VERSION 5.7 ;
BUSBITCHARS "[]" ;
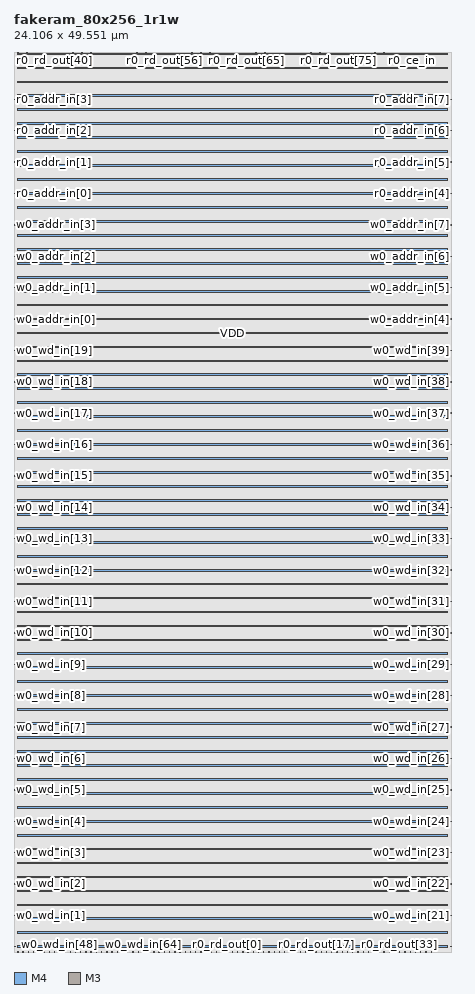
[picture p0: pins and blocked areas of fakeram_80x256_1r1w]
MACRO fakeram_80x256_1r1w
  FOREIGN fakeram_80x256_1r1w 0 0 ;
  SYMMETRY X Y R90 ;
  SIZE 24.106 BY 49.551 ;
  CLASS BLOCK ;
  PIN w0_wd_in[0]
    DIRECTION INPUT ;
    USE SIGNAL ;
    SHAPE ABUTMENT ;
    PORT
      LAYER M4 ;
      RECT 0.000 0.276 0.072 0.300 ;
    END
  END w0_wd_in[0]
  PIN w0_wd_in[1]
    DIRECTION INPUT ;
    USE SIGNAL ;
    SHAPE ABUTMENT ;
    PORT
      LAYER M4 ;
      RECT 0.000 2.004 0.072 2.028 ;
    END
  END w0_wd_in[1]
  PIN w0_wd_in[2]
    DIRECTION INPUT ;
    USE SIGNAL ;
    SHAPE ABUTMENT ;
    PORT
      LAYER M4 ;
      RECT 0.000 3.732 0.072 3.756 ;
    END
  END w0_wd_in[2]
  PIN w0_wd_in[3]
    DIRECTION INPUT ;
    USE SIGNAL ;
    SHAPE ABUTMENT ;
    PORT
      LAYER M4 ;
      RECT 0.000 5.460 0.072 5.484 ;
    END
  END w0_wd_in[3]
  PIN w0_wd_in[4]
    DIRECTION INPUT ;
    USE SIGNAL ;
    SHAPE ABUTMENT ;
    PORT
      LAYER M4 ;
      RECT 0.000 7.188 0.072 7.212 ;
    END
  END w0_wd_in[4]
  PIN w0_wd_in[5]
    DIRECTION INPUT ;
    USE SIGNAL ;
    SHAPE ABUTMENT ;
    PORT
      LAYER M4 ;
      RECT 0.000 8.916 0.072 8.940 ;
    END
  END w0_wd_in[5]
  PIN w0_wd_in[6]
    DIRECTION INPUT ;
    USE SIGNAL ;
    SHAPE ABUTMENT ;
    PORT
      LAYER M4 ;
      RECT 0.000 10.644 0.072 10.668 ;
    END
  END w0_wd_in[6]
  PIN w0_wd_in[7]
    DIRECTION INPUT ;
    USE SIGNAL ;
    SHAPE ABUTMENT ;
    PORT
      LAYER M4 ;
      RECT 0.000 12.372 0.072 12.396 ;
    END
  END w0_wd_in[7]
  PIN w0_wd_in[8]
    DIRECTION INPUT ;
    USE SIGNAL ;
    SHAPE ABUTMENT ;
    PORT
      LAYER M4 ;
      RECT 0.000 14.100 0.072 14.124 ;
    END
  END w0_wd_in[8]
  PIN w0_wd_in[9]
    DIRECTION INPUT ;
    USE SIGNAL ;
    SHAPE ABUTMENT ;
    PORT
      LAYER M4 ;
      RECT 0.000 15.828 0.072 15.852 ;
    END
  END w0_wd_in[9]
  PIN w0_wd_in[10]
    DIRECTION INPUT ;
    USE SIGNAL ;
    SHAPE ABUTMENT ;
    PORT
      LAYER M4 ;
      RECT 0.000 17.556 0.072 17.580 ;
    END
  END w0_wd_in[10]
  PIN w0_wd_in[11]
    DIRECTION INPUT ;
    USE SIGNAL ;
    SHAPE ABUTMENT ;
    PORT
      LAYER M4 ;
      RECT 0.000 19.284 0.072 19.308 ;
    END
  END w0_wd_in[11]
  PIN w0_wd_in[12]
    DIRECTION INPUT ;
    USE SIGNAL ;
    SHAPE ABUTMENT ;
    PORT
      LAYER M4 ;
      RECT 0.000 21.012 0.072 21.036 ;
    END
  END w0_wd_in[12]
  PIN w0_wd_in[13]
    DIRECTION INPUT ;
    USE SIGNAL ;
    SHAPE ABUTMENT ;
    PORT
      LAYER M4 ;
      RECT 0.000 22.740 0.072 22.764 ;
    END
  END w0_wd_in[13]
  PIN w0_wd_in[14]
    DIRECTION INPUT ;
    USE SIGNAL ;
    SHAPE ABUTMENT ;
    PORT
      LAYER M4 ;
      RECT 0.000 24.468 0.072 24.492 ;
    END
  END w0_wd_in[14]
  PIN w0_wd_in[15]
    DIRECTION INPUT ;
    USE SIGNAL ;
    SHAPE ABUTMENT ;
    PORT
      LAYER M4 ;
      RECT 0.000 26.196 0.072 26.220 ;
    END
  END w0_wd_in[15]
  PIN w0_wd_in[16]
    DIRECTION INPUT ;
    USE SIGNAL ;
    SHAPE ABUTMENT ;
    PORT
      LAYER M4 ;
      RECT 0.000 27.924 0.072 27.948 ;
    END
  END w0_wd_in[16]
  PIN w0_wd_in[17]
    DIRECTION INPUT ;
    USE SIGNAL ;
    SHAPE ABUTMENT ;
    PORT
      LAYER M4 ;
      RECT 0.000 29.652 0.072 29.676 ;
    END
  END w0_wd_in[17]
  PIN w0_wd_in[18]
    DIRECTION INPUT ;
    USE SIGNAL ;
    SHAPE ABUTMENT ;
    PORT
      LAYER M4 ;
      RECT 0.000 31.380 0.072 31.404 ;
    END
  END w0_wd_in[18]
  PIN w0_wd_in[19]
    DIRECTION INPUT ;
    USE SIGNAL ;
    SHAPE ABUTMENT ;
    PORT
      LAYER M4 ;
      RECT 0.000 33.108 0.072 33.132 ;
    END
  END w0_wd_in[19]
  PIN w0_wd_in[20]
    DIRECTION INPUT ;
    USE SIGNAL ;
    SHAPE ABUTMENT ;
    PORT
      LAYER M4 ;
      RECT 24.034 0.276 24.106 0.300 ;
    END
  END w0_wd_in[20]
  PIN w0_wd_in[21]
    DIRECTION INPUT ;
    USE SIGNAL ;
    SHAPE ABUTMENT ;
    PORT
      LAYER M4 ;
      RECT 24.034 2.004 24.106 2.028 ;
    END
  END w0_wd_in[21]
  PIN w0_wd_in[22]
    DIRECTION INPUT ;
    USE SIGNAL ;
    SHAPE ABUTMENT ;
    PORT
      LAYER M4 ;
      RECT 24.034 3.732 24.106 3.756 ;
    END
  END w0_wd_in[22]
  PIN w0_wd_in[23]
    DIRECTION INPUT ;
    USE SIGNAL ;
    SHAPE ABUTMENT ;
    PORT
      LAYER M4 ;
      RECT 24.034 5.460 24.106 5.484 ;
    END
  END w0_wd_in[23]
  PIN w0_wd_in[24]
    DIRECTION INPUT ;
    USE SIGNAL ;
    SHAPE ABUTMENT ;
    PORT
      LAYER M4 ;
      RECT 24.034 7.188 24.106 7.212 ;
    END
  END w0_wd_in[24]
  PIN w0_wd_in[25]
    DIRECTION INPUT ;
    USE SIGNAL ;
    SHAPE ABUTMENT ;
    PORT
      LAYER M4 ;
      RECT 24.034 8.916 24.106 8.940 ;
    END
  END w0_wd_in[25]
  PIN w0_wd_in[26]
    DIRECTION INPUT ;
    USE SIGNAL ;
    SHAPE ABUTMENT ;
    PORT
      LAYER M4 ;
      RECT 24.034 10.644 24.106 10.668 ;
    END
  END w0_wd_in[26]
  PIN w0_wd_in[27]
    DIRECTION INPUT ;
    USE SIGNAL ;
    SHAPE ABUTMENT ;
    PORT
      LAYER M4 ;
      RECT 24.034 12.372 24.106 12.396 ;
    END
  END w0_wd_in[27]
  PIN w0_wd_in[28]
    DIRECTION INPUT ;
    USE SIGNAL ;
    SHAPE ABUTMENT ;
    PORT
      LAYER M4 ;
      RECT 24.034 14.100 24.106 14.124 ;
    END
  END w0_wd_in[28]
  PIN w0_wd_in[29]
    DIRECTION INPUT ;
    USE SIGNAL ;
    SHAPE ABUTMENT ;
    PORT
      LAYER M4 ;
      RECT 24.034 15.828 24.106 15.852 ;
    END
  END w0_wd_in[29]
  PIN w0_wd_in[30]
    DIRECTION INPUT ;
    USE SIGNAL ;
    SHAPE ABUTMENT ;
    PORT
      LAYER M4 ;
      RECT 24.034 17.556 24.106 17.580 ;
    END
  END w0_wd_in[30]
  PIN w0_wd_in[31]
    DIRECTION INPUT ;
    USE SIGNAL ;
    SHAPE ABUTMENT ;
    PORT
      LAYER M4 ;
      RECT 24.034 19.284 24.106 19.308 ;
    END
  END w0_wd_in[31]
  PIN w0_wd_in[32]
    DIRECTION INPUT ;
    USE SIGNAL ;
    SHAPE ABUTMENT ;
    PORT
      LAYER M4 ;
      RECT 24.034 21.012 24.106 21.036 ;
    END
  END w0_wd_in[32]
  PIN w0_wd_in[33]
    DIRECTION INPUT ;
    USE SIGNAL ;
    SHAPE ABUTMENT ;
    PORT
      LAYER M4 ;
      RECT 24.034 22.740 24.106 22.764 ;
    END
  END w0_wd_in[33]
  PIN w0_wd_in[34]
    DIRECTION INPUT ;
    USE SIGNAL ;
    SHAPE ABUTMENT ;
    PORT
      LAYER M4 ;
      RECT 24.034 24.468 24.106 24.492 ;
    END
  END w0_wd_in[34]
  PIN w0_wd_in[35]
    DIRECTION INPUT ;
    USE SIGNAL ;
    SHAPE ABUTMENT ;
    PORT
      LAYER M4 ;
      RECT 24.034 26.196 24.106 26.220 ;
    END
  END w0_wd_in[35]
  PIN w0_wd_in[36]
    DIRECTION INPUT ;
    USE SIGNAL ;
    SHAPE ABUTMENT ;
    PORT
      LAYER M4 ;
      RECT 24.034 27.924 24.106 27.948 ;
    END
  END w0_wd_in[36]
  PIN w0_wd_in[37]
    DIRECTION INPUT ;
    USE SIGNAL ;
    SHAPE ABUTMENT ;
    PORT
      LAYER M4 ;
      RECT 24.034 29.652 24.106 29.676 ;
    END
  END w0_wd_in[37]
  PIN w0_wd_in[38]
    DIRECTION INPUT ;
    USE SIGNAL ;
    SHAPE ABUTMENT ;
    PORT
      LAYER M4 ;
      RECT 24.034 31.380 24.106 31.404 ;
    END
  END w0_wd_in[38]
  PIN w0_wd_in[39]
    DIRECTION INPUT ;
    USE SIGNAL ;
    SHAPE ABUTMENT ;
    PORT
      LAYER M4 ;
      RECT 24.034 33.108 24.106 33.132 ;
    END
  END w0_wd_in[39]
  PIN w0_wd_in[40]
    DIRECTION OUTPUT ;
    USE SIGNAL ;
    SHAPE ABUTMENT ;
    PORT
      LAYER M3 ;
      RECT 0.207 0.000 0.225 0.054 ;
    END
  END w0_wd_in[40]
  PIN w0_wd_in[41]
    DIRECTION OUTPUT ;
    USE SIGNAL ;
    SHAPE ABUTMENT ;
    PORT
      LAYER M3 ;
      RECT 0.495 0.000 0.513 0.054 ;
    END
  END w0_wd_in[41]
  PIN w0_wd_in[42]
    DIRECTION OUTPUT ;
    USE SIGNAL ;
    SHAPE ABUTMENT ;
    PORT
      LAYER M3 ;
      RECT 0.783 0.000 0.801 0.054 ;
    END
  END w0_wd_in[42]
  PIN w0_wd_in[43]
    DIRECTION OUTPUT ;
    USE SIGNAL ;
    SHAPE ABUTMENT ;
    PORT
      LAYER M3 ;
      RECT 1.071 0.000 1.089 0.054 ;
    END
  END w0_wd_in[43]
  PIN w0_wd_in[44]
    DIRECTION OUTPUT ;
    USE SIGNAL ;
    SHAPE ABUTMENT ;
    PORT
      LAYER M3 ;
      RECT 1.359 0.000 1.377 0.054 ;
    END
  END w0_wd_in[44]
  PIN w0_wd_in[45]
    DIRECTION OUTPUT ;
    USE SIGNAL ;
    SHAPE ABUTMENT ;
    PORT
      LAYER M3 ;
      RECT 1.647 0.000 1.665 0.054 ;
    END
  END w0_wd_in[45]
  PIN w0_wd_in[46]
    DIRECTION OUTPUT ;
    USE SIGNAL ;
    SHAPE ABUTMENT ;
    PORT
      LAYER M3 ;
      RECT 1.935 0.000 1.953 0.054 ;
    END
  END w0_wd_in[46]
  PIN w0_wd_in[47]
    DIRECTION OUTPUT ;
    USE SIGNAL ;
    SHAPE ABUTMENT ;
    PORT
      LAYER M3 ;
      RECT 2.223 0.000 2.241 0.054 ;
    END
  END w0_wd_in[47]
  PIN w0_wd_in[48]
    DIRECTION OUTPUT ;
    USE SIGNAL ;
    SHAPE ABUTMENT ;
    PORT
      LAYER M3 ;
      RECT 2.511 0.000 2.529 0.054 ;
    END
  END w0_wd_in[48]
  PIN w0_wd_in[49]
    DIRECTION OUTPUT ;
    USE SIGNAL ;
    SHAPE ABUTMENT ;
    PORT
      LAYER M3 ;
      RECT 2.799 0.000 2.817 0.054 ;
    END
  END w0_wd_in[49]
  PIN w0_wd_in[50]
    DIRECTION OUTPUT ;
    USE SIGNAL ;
    SHAPE ABUTMENT ;
    PORT
      LAYER M3 ;
      RECT 3.087 0.000 3.105 0.054 ;
    END
  END w0_wd_in[50]
  PIN w0_wd_in[51]
    DIRECTION OUTPUT ;
    USE SIGNAL ;
    SHAPE ABUTMENT ;
    PORT
      LAYER M3 ;
      RECT 3.375 0.000 3.393 0.054 ;
    END
  END w0_wd_in[51]
  PIN w0_wd_in[52]
    DIRECTION OUTPUT ;
    USE SIGNAL ;
    SHAPE ABUTMENT ;
    PORT
      LAYER M3 ;
      RECT 3.663 0.000 3.681 0.054 ;
    END
  END w0_wd_in[52]
  PIN w0_wd_in[53]
    DIRECTION OUTPUT ;
    USE SIGNAL ;
    SHAPE ABUTMENT ;
    PORT
      LAYER M3 ;
      RECT 3.951 0.000 3.969 0.054 ;
    END
  END w0_wd_in[53]
  PIN w0_wd_in[54]
    DIRECTION OUTPUT ;
    USE SIGNAL ;
    SHAPE ABUTMENT ;
    PORT
      LAYER M3 ;
      RECT 4.239 0.000 4.257 0.054 ;
    END
  END w0_wd_in[54]
  PIN w0_wd_in[55]
    DIRECTION OUTPUT ;
    USE SIGNAL ;
    SHAPE ABUTMENT ;
    PORT
      LAYER M3 ;
      RECT 4.527 0.000 4.545 0.054 ;
    END
  END w0_wd_in[55]
  PIN w0_wd_in[56]
    DIRECTION OUTPUT ;
    USE SIGNAL ;
    SHAPE ABUTMENT ;
    PORT
      LAYER M3 ;
      RECT 4.815 0.000 4.833 0.054 ;
    END
  END w0_wd_in[56]
  PIN w0_wd_in[57]
    DIRECTION OUTPUT ;
    USE SIGNAL ;
    SHAPE ABUTMENT ;
    PORT
      LAYER M3 ;
      RECT 5.103 0.000 5.121 0.054 ;
    END
  END w0_wd_in[57]
  PIN w0_wd_in[58]
    DIRECTION OUTPUT ;
    USE SIGNAL ;
    SHAPE ABUTMENT ;
    PORT
      LAYER M3 ;
      RECT 5.391 0.000 5.409 0.054 ;
    END
  END w0_wd_in[58]
  PIN w0_wd_in[59]
    DIRECTION OUTPUT ;
    USE SIGNAL ;
    SHAPE ABUTMENT ;
    PORT
      LAYER M3 ;
      RECT 5.679 0.000 5.697 0.054 ;
    END
  END w0_wd_in[59]
  PIN w0_wd_in[60]
    DIRECTION OUTPUT ;
    USE SIGNAL ;
    SHAPE ABUTMENT ;
    PORT
      LAYER M3 ;
      RECT 5.967 0.000 5.985 0.054 ;
    END
  END w0_wd_in[60]
  PIN w0_wd_in[61]
    DIRECTION OUTPUT ;
    USE SIGNAL ;
    SHAPE ABUTMENT ;
    PORT
      LAYER M3 ;
      RECT 6.255 0.000 6.273 0.054 ;
    END
  END w0_wd_in[61]
  PIN w0_wd_in[62]
    DIRECTION OUTPUT ;
    USE SIGNAL ;
    SHAPE ABUTMENT ;
    PORT
      LAYER M3 ;
      RECT 6.543 0.000 6.561 0.054 ;
    END
  END w0_wd_in[62]
  PIN w0_wd_in[63]
    DIRECTION OUTPUT ;
    USE SIGNAL ;
    SHAPE ABUTMENT ;
    PORT
      LAYER M3 ;
      RECT 6.831 0.000 6.849 0.054 ;
    END
  END w0_wd_in[63]
  PIN w0_wd_in[64]
    DIRECTION OUTPUT ;
    USE SIGNAL ;
    SHAPE ABUTMENT ;
    PORT
      LAYER M3 ;
      RECT 7.119 0.000 7.137 0.054 ;
    END
  END w0_wd_in[64]
  PIN w0_wd_in[65]
    DIRECTION OUTPUT ;
    USE SIGNAL ;
    SHAPE ABUTMENT ;
    PORT
      LAYER M3 ;
      RECT 7.407 0.000 7.425 0.054 ;
    END
  END w0_wd_in[65]
  PIN w0_wd_in[66]
    DIRECTION OUTPUT ;
    USE SIGNAL ;
    SHAPE ABUTMENT ;
    PORT
      LAYER M3 ;
      RECT 7.695 0.000 7.713 0.054 ;
    END
  END w0_wd_in[66]
  PIN w0_wd_in[67]
    DIRECTION OUTPUT ;
    USE SIGNAL ;
    SHAPE ABUTMENT ;
    PORT
      LAYER M3 ;
      RECT 7.983 0.000 8.001 0.054 ;
    END
  END w0_wd_in[67]
  PIN w0_wd_in[68]
    DIRECTION OUTPUT ;
    USE SIGNAL ;
    SHAPE ABUTMENT ;
    PORT
      LAYER M3 ;
      RECT 8.271 0.000 8.289 0.054 ;
    END
  END w0_wd_in[68]
  PIN w0_wd_in[69]
    DIRECTION OUTPUT ;
    USE SIGNAL ;
    SHAPE ABUTMENT ;
    PORT
      LAYER M3 ;
      RECT 8.559 0.000 8.577 0.054 ;
    END
  END w0_wd_in[69]
  PIN w0_wd_in[70]
    DIRECTION OUTPUT ;
    USE SIGNAL ;
    SHAPE ABUTMENT ;
    PORT
      LAYER M3 ;
      RECT 8.847 0.000 8.865 0.054 ;
    END
  END w0_wd_in[70]
  PIN w0_wd_in[71]
    DIRECTION OUTPUT ;
    USE SIGNAL ;
    SHAPE ABUTMENT ;
    PORT
      LAYER M3 ;
      RECT 9.135 0.000 9.153 0.054 ;
    END
  END w0_wd_in[71]
  PIN w0_wd_in[72]
    DIRECTION OUTPUT ;
    USE SIGNAL ;
    SHAPE ABUTMENT ;
    PORT
      LAYER M3 ;
      RECT 9.423 0.000 9.441 0.054 ;
    END
  END w0_wd_in[72]
  PIN w0_wd_in[73]
    DIRECTION OUTPUT ;
    USE SIGNAL ;
    SHAPE ABUTMENT ;
    PORT
      LAYER M3 ;
      RECT 9.711 0.000 9.729 0.054 ;
    END
  END w0_wd_in[73]
  PIN w0_wd_in[74]
    DIRECTION OUTPUT ;
    USE SIGNAL ;
    SHAPE ABUTMENT ;
    PORT
      LAYER M3 ;
      RECT 9.999 0.000 10.017 0.054 ;
    END
  END w0_wd_in[74]
  PIN w0_wd_in[75]
    DIRECTION OUTPUT ;
    USE SIGNAL ;
    SHAPE ABUTMENT ;
    PORT
      LAYER M3 ;
      RECT 10.287 0.000 10.305 0.054 ;
    END
  END w0_wd_in[75]
  PIN w0_wd_in[76]
    DIRECTION OUTPUT ;
    USE SIGNAL ;
    SHAPE ABUTMENT ;
    PORT
      LAYER M3 ;
      RECT 10.575 0.000 10.593 0.054 ;
    END
  END w0_wd_in[76]
  PIN w0_wd_in[77]
    DIRECTION OUTPUT ;
    USE SIGNAL ;
    SHAPE ABUTMENT ;
    PORT
      LAYER M3 ;
      RECT 10.863 0.000 10.881 0.054 ;
    END
  END w0_wd_in[77]
  PIN w0_wd_in[78]
    DIRECTION OUTPUT ;
    USE SIGNAL ;
    SHAPE ABUTMENT ;
    PORT
      LAYER M3 ;
      RECT 11.151 0.000 11.169 0.054 ;
    END
  END w0_wd_in[78]
  PIN w0_wd_in[79]
    DIRECTION OUTPUT ;
    USE SIGNAL ;
    SHAPE ABUTMENT ;
    PORT
      LAYER M3 ;
      RECT 11.439 0.000 11.457 0.054 ;
    END
  END w0_wd_in[79]
  PIN r0_rd_out[0]
    DIRECTION OUTPUT ;
    USE SIGNAL ;
    SHAPE ABUTMENT ;
    PORT
      LAYER M3 ;
      RECT 11.727 0.000 11.745 0.054 ;
    END
  END r0_rd_out[0]
  PIN r0_rd_out[1]
    DIRECTION OUTPUT ;
    USE SIGNAL ;
    SHAPE ABUTMENT ;
    PORT
      LAYER M3 ;
      RECT 12.015 0.000 12.033 0.054 ;
    END
  END r0_rd_out[1]
  PIN r0_rd_out[2]
    DIRECTION OUTPUT ;
    USE SIGNAL ;
    SHAPE ABUTMENT ;
    PORT
      LAYER M3 ;
      RECT 12.303 0.000 12.321 0.054 ;
    END
  END r0_rd_out[2]
  PIN r0_rd_out[3]
    DIRECTION OUTPUT ;
    USE SIGNAL ;
    SHAPE ABUTMENT ;
    PORT
      LAYER M3 ;
      RECT 12.591 0.000 12.609 0.054 ;
    END
  END r0_rd_out[3]
  PIN r0_rd_out[4]
    DIRECTION OUTPUT ;
    USE SIGNAL ;
    SHAPE ABUTMENT ;
    PORT
      LAYER M3 ;
      RECT 12.879 0.000 12.897 0.054 ;
    END
  END r0_rd_out[4]
  PIN r0_rd_out[5]
    DIRECTION OUTPUT ;
    USE SIGNAL ;
    SHAPE ABUTMENT ;
    PORT
      LAYER M3 ;
      RECT 13.167 0.000 13.185 0.054 ;
    END
  END r0_rd_out[5]
  PIN r0_rd_out[6]
    DIRECTION OUTPUT ;
    USE SIGNAL ;
    SHAPE ABUTMENT ;
    PORT
      LAYER M3 ;
      RECT 13.455 0.000 13.473 0.054 ;
    END
  END r0_rd_out[6]
  PIN r0_rd_out[7]
    DIRECTION OUTPUT ;
    USE SIGNAL ;
    SHAPE ABUTMENT ;
    PORT
      LAYER M3 ;
      RECT 13.743 0.000 13.761 0.054 ;
    END
  END r0_rd_out[7]
  PIN r0_rd_out[8]
    DIRECTION OUTPUT ;
    USE SIGNAL ;
    SHAPE ABUTMENT ;
    PORT
      LAYER M3 ;
      RECT 14.031 0.000 14.049 0.054 ;
    END
  END r0_rd_out[8]
  PIN r0_rd_out[9]
    DIRECTION OUTPUT ;
    USE SIGNAL ;
    SHAPE ABUTMENT ;
    PORT
      LAYER M3 ;
      RECT 14.319 0.000 14.337 0.054 ;
    END
  END r0_rd_out[9]
  PIN r0_rd_out[10]
    DIRECTION OUTPUT ;
    USE SIGNAL ;
    SHAPE ABUTMENT ;
    PORT
      LAYER M3 ;
      RECT 14.607 0.000 14.625 0.054 ;
    END
  END r0_rd_out[10]
  PIN r0_rd_out[11]
    DIRECTION OUTPUT ;
    USE SIGNAL ;
    SHAPE ABUTMENT ;
    PORT
      LAYER M3 ;
      RECT 14.895 0.000 14.913 0.054 ;
    END
  END r0_rd_out[11]
  PIN r0_rd_out[12]
    DIRECTION OUTPUT ;
    USE SIGNAL ;
    SHAPE ABUTMENT ;
    PORT
      LAYER M3 ;
      RECT 15.183 0.000 15.201 0.054 ;
    END
  END r0_rd_out[12]
  PIN r0_rd_out[13]
    DIRECTION OUTPUT ;
    USE SIGNAL ;
    SHAPE ABUTMENT ;
    PORT
      LAYER M3 ;
      RECT 15.471 0.000 15.489 0.054 ;
    END
  END r0_rd_out[13]
  PIN r0_rd_out[14]
    DIRECTION OUTPUT ;
    USE SIGNAL ;
    SHAPE ABUTMENT ;
    PORT
      LAYER M3 ;
      RECT 15.759 0.000 15.777 0.054 ;
    END
  END r0_rd_out[14]
  PIN r0_rd_out[15]
    DIRECTION OUTPUT ;
    USE SIGNAL ;
    SHAPE ABUTMENT ;
    PORT
      LAYER M3 ;
      RECT 16.047 0.000 16.065 0.054 ;
    END
  END r0_rd_out[15]
  PIN r0_rd_out[16]
    DIRECTION OUTPUT ;
    USE SIGNAL ;
    SHAPE ABUTMENT ;
    PORT
      LAYER M3 ;
      RECT 16.335 0.000 16.353 0.054 ;
    END
  END r0_rd_out[16]
  PIN r0_rd_out[17]
    DIRECTION OUTPUT ;
    USE SIGNAL ;
    SHAPE ABUTMENT ;
    PORT
      LAYER M3 ;
      RECT 16.623 0.000 16.641 0.054 ;
    END
  END r0_rd_out[17]
  PIN r0_rd_out[18]
    DIRECTION OUTPUT ;
    USE SIGNAL ;
    SHAPE ABUTMENT ;
    PORT
      LAYER M3 ;
      RECT 16.911 0.000 16.929 0.054 ;
    END
  END r0_rd_out[18]
  PIN r0_rd_out[19]
    DIRECTION OUTPUT ;
    USE SIGNAL ;
    SHAPE ABUTMENT ;
    PORT
      LAYER M3 ;
      RECT 17.199 0.000 17.217 0.054 ;
    END
  END r0_rd_out[19]
  PIN r0_rd_out[20]
    DIRECTION OUTPUT ;
    USE SIGNAL ;
    SHAPE ABUTMENT ;
    PORT
      LAYER M3 ;
      RECT 17.487 0.000 17.505 0.054 ;
    END
  END r0_rd_out[20]
  PIN r0_rd_out[21]
    DIRECTION OUTPUT ;
    USE SIGNAL ;
    SHAPE ABUTMENT ;
    PORT
      LAYER M3 ;
      RECT 17.775 0.000 17.793 0.054 ;
    END
  END r0_rd_out[21]
  PIN r0_rd_out[22]
    DIRECTION OUTPUT ;
    USE SIGNAL ;
    SHAPE ABUTMENT ;
    PORT
      LAYER M3 ;
      RECT 18.063 0.000 18.081 0.054 ;
    END
  END r0_rd_out[22]
  PIN r0_rd_out[23]
    DIRECTION OUTPUT ;
    USE SIGNAL ;
    SHAPE ABUTMENT ;
    PORT
      LAYER M3 ;
      RECT 18.351 0.000 18.369 0.054 ;
    END
  END r0_rd_out[23]
  PIN r0_rd_out[24]
    DIRECTION OUTPUT ;
    USE SIGNAL ;
    SHAPE ABUTMENT ;
    PORT
      LAYER M3 ;
      RECT 18.639 0.000 18.657 0.054 ;
    END
  END r0_rd_out[24]
  PIN r0_rd_out[25]
    DIRECTION OUTPUT ;
    USE SIGNAL ;
    SHAPE ABUTMENT ;
    PORT
      LAYER M3 ;
      RECT 18.927 0.000 18.945 0.054 ;
    END
  END r0_rd_out[25]
  PIN r0_rd_out[26]
    DIRECTION OUTPUT ;
    USE SIGNAL ;
    SHAPE ABUTMENT ;
    PORT
      LAYER M3 ;
      RECT 19.215 0.000 19.233 0.054 ;
    END
  END r0_rd_out[26]
  PIN r0_rd_out[27]
    DIRECTION OUTPUT ;
    USE SIGNAL ;
    SHAPE ABUTMENT ;
    PORT
      LAYER M3 ;
      RECT 19.503 0.000 19.521 0.054 ;
    END
  END r0_rd_out[27]
  PIN r0_rd_out[28]
    DIRECTION OUTPUT ;
    USE SIGNAL ;
    SHAPE ABUTMENT ;
    PORT
      LAYER M3 ;
      RECT 19.791 0.000 19.809 0.054 ;
    END
  END r0_rd_out[28]
  PIN r0_rd_out[29]
    DIRECTION OUTPUT ;
    USE SIGNAL ;
    SHAPE ABUTMENT ;
    PORT
      LAYER M3 ;
      RECT 20.079 0.000 20.097 0.054 ;
    END
  END r0_rd_out[29]
  PIN r0_rd_out[30]
    DIRECTION OUTPUT ;
    USE SIGNAL ;
    SHAPE ABUTMENT ;
    PORT
      LAYER M3 ;
      RECT 20.367 0.000 20.385 0.054 ;
    END
  END r0_rd_out[30]
  PIN r0_rd_out[31]
    DIRECTION OUTPUT ;
    USE SIGNAL ;
    SHAPE ABUTMENT ;
    PORT
      LAYER M3 ;
      RECT 20.655 0.000 20.673 0.054 ;
    END
  END r0_rd_out[31]
  PIN r0_rd_out[32]
    DIRECTION OUTPUT ;
    USE SIGNAL ;
    SHAPE ABUTMENT ;
    PORT
      LAYER M3 ;
      RECT 20.943 0.000 20.961 0.054 ;
    END
  END r0_rd_out[32]
  PIN r0_rd_out[33]
    DIRECTION OUTPUT ;
    USE SIGNAL ;
    SHAPE ABUTMENT ;
    PORT
      LAYER M3 ;
      RECT 21.231 0.000 21.249 0.054 ;
    END
  END r0_rd_out[33]
  PIN r0_rd_out[34]
    DIRECTION OUTPUT ;
    USE SIGNAL ;
    SHAPE ABUTMENT ;
    PORT
      LAYER M3 ;
      RECT 21.519 0.000 21.537 0.054 ;
    END
  END r0_rd_out[34]
  PIN r0_rd_out[35]
    DIRECTION OUTPUT ;
    USE SIGNAL ;
    SHAPE ABUTMENT ;
    PORT
      LAYER M3 ;
      RECT 21.807 0.000 21.825 0.054 ;
    END
  END r0_rd_out[35]
  PIN r0_rd_out[36]
    DIRECTION OUTPUT ;
    USE SIGNAL ;
    SHAPE ABUTMENT ;
    PORT
      LAYER M3 ;
      RECT 22.095 0.000 22.113 0.054 ;
    END
  END r0_rd_out[36]
  PIN r0_rd_out[37]
    DIRECTION OUTPUT ;
    USE SIGNAL ;
    SHAPE ABUTMENT ;
    PORT
      LAYER M3 ;
      RECT 22.383 0.000 22.401 0.054 ;
    END
  END r0_rd_out[37]
  PIN r0_rd_out[38]
    DIRECTION OUTPUT ;
    USE SIGNAL ;
    SHAPE ABUTMENT ;
    PORT
      LAYER M3 ;
      RECT 22.671 0.000 22.689 0.054 ;
    END
  END r0_rd_out[38]
  PIN r0_rd_out[39]
    DIRECTION OUTPUT ;
    USE SIGNAL ;
    SHAPE ABUTMENT ;
    PORT
      LAYER M3 ;
      RECT 22.959 0.000 22.977 0.054 ;
    END
  END r0_rd_out[39]
  PIN r0_rd_out[40]
    DIRECTION OUTPUT ;
    USE SIGNAL ;
    SHAPE ABUTMENT ;
    PORT
      LAYER M3 ;
      RECT 0.207 49.497 0.225 49.551 ;
    END
  END r0_rd_out[40]
  PIN r0_rd_out[41]
    DIRECTION OUTPUT ;
    USE SIGNAL ;
    SHAPE ABUTMENT ;
    PORT
      LAYER M3 ;
      RECT 0.711 49.497 0.729 49.551 ;
    END
  END r0_rd_out[41]
  PIN r0_rd_out[42]
    DIRECTION OUTPUT ;
    USE SIGNAL ;
    SHAPE ABUTMENT ;
    PORT
      LAYER M3 ;
      RECT 1.215 49.497 1.233 49.551 ;
    END
  END r0_rd_out[42]
  PIN r0_rd_out[43]
    DIRECTION OUTPUT ;
    USE SIGNAL ;
    SHAPE ABUTMENT ;
    PORT
      LAYER M3 ;
      RECT 1.719 49.497 1.737 49.551 ;
    END
  END r0_rd_out[43]
  PIN r0_rd_out[44]
    DIRECTION OUTPUT ;
    USE SIGNAL ;
    SHAPE ABUTMENT ;
    PORT
      LAYER M3 ;
      RECT 2.223 49.497 2.241 49.551 ;
    END
  END r0_rd_out[44]
  PIN r0_rd_out[45]
    DIRECTION OUTPUT ;
    USE SIGNAL ;
    SHAPE ABUTMENT ;
    PORT
      LAYER M3 ;
      RECT 2.727 49.497 2.745 49.551 ;
    END
  END r0_rd_out[45]
  PIN r0_rd_out[46]
    DIRECTION OUTPUT ;
    USE SIGNAL ;
    SHAPE ABUTMENT ;
    PORT
      LAYER M3 ;
      RECT 3.231 49.497 3.249 49.551 ;
    END
  END r0_rd_out[46]
  PIN r0_rd_out[47]
    DIRECTION OUTPUT ;
    USE SIGNAL ;
    SHAPE ABUTMENT ;
    PORT
      LAYER M3 ;
      RECT 3.735 49.497 3.753 49.551 ;
    END
  END r0_rd_out[47]
  PIN r0_rd_out[48]
    DIRECTION OUTPUT ;
    USE SIGNAL ;
    SHAPE ABUTMENT ;
    PORT
      LAYER M3 ;
      RECT 4.239 49.497 4.257 49.551 ;
    END
  END r0_rd_out[48]
  PIN r0_rd_out[49]
    DIRECTION OUTPUT ;
    USE SIGNAL ;
    SHAPE ABUTMENT ;
    PORT
      LAYER M3 ;
      RECT 4.743 49.497 4.761 49.551 ;
    END
  END r0_rd_out[49]
  PIN r0_rd_out[50]
    DIRECTION OUTPUT ;
    USE SIGNAL ;
    SHAPE ABUTMENT ;
    PORT
      LAYER M3 ;
      RECT 5.247 49.497 5.265 49.551 ;
    END
  END r0_rd_out[50]
  PIN r0_rd_out[51]
    DIRECTION OUTPUT ;
    USE SIGNAL ;
    SHAPE ABUTMENT ;
    PORT
      LAYER M3 ;
      RECT 5.751 49.497 5.769 49.551 ;
    END
  END r0_rd_out[51]
  PIN r0_rd_out[52]
    DIRECTION OUTPUT ;
    USE SIGNAL ;
    SHAPE ABUTMENT ;
    PORT
      LAYER M3 ;
      RECT 6.255 49.497 6.273 49.551 ;
    END
  END r0_rd_out[52]
  PIN r0_rd_out[53]
    DIRECTION OUTPUT ;
    USE SIGNAL ;
    SHAPE ABUTMENT ;
    PORT
      LAYER M3 ;
      RECT 6.759 49.497 6.777 49.551 ;
    END
  END r0_rd_out[53]
  PIN r0_rd_out[54]
    DIRECTION OUTPUT ;
    USE SIGNAL ;
    SHAPE ABUTMENT ;
    PORT
      LAYER M3 ;
      RECT 7.263 49.497 7.281 49.551 ;
    END
  END r0_rd_out[54]
  PIN r0_rd_out[55]
    DIRECTION OUTPUT ;
    USE SIGNAL ;
    SHAPE ABUTMENT ;
    PORT
      LAYER M3 ;
      RECT 7.767 49.497 7.785 49.551 ;
    END
  END r0_rd_out[55]
  PIN r0_rd_out[56]
    DIRECTION OUTPUT ;
    USE SIGNAL ;
    SHAPE ABUTMENT ;
    PORT
      LAYER M3 ;
      RECT 8.271 49.497 8.289 49.551 ;
    END
  END r0_rd_out[56]
  PIN r0_rd_out[57]
    DIRECTION OUTPUT ;
    USE SIGNAL ;
    SHAPE ABUTMENT ;
    PORT
      LAYER M3 ;
      RECT 8.775 49.497 8.793 49.551 ;
    END
  END r0_rd_out[57]
  PIN r0_rd_out[58]
    DIRECTION OUTPUT ;
    USE SIGNAL ;
    SHAPE ABUTMENT ;
    PORT
      LAYER M3 ;
      RECT 9.279 49.497 9.297 49.551 ;
    END
  END r0_rd_out[58]
  PIN r0_rd_out[59]
    DIRECTION OUTPUT ;
    USE SIGNAL ;
    SHAPE ABUTMENT ;
    PORT
      LAYER M3 ;
      RECT 9.783 49.497 9.801 49.551 ;
    END
  END r0_rd_out[59]
  PIN r0_rd_out[60]
    DIRECTION OUTPUT ;
    USE SIGNAL ;
    SHAPE ABUTMENT ;
    PORT
      LAYER M3 ;
      RECT 10.287 49.497 10.305 49.551 ;
    END
  END r0_rd_out[60]
  PIN r0_rd_out[61]
    DIRECTION OUTPUT ;
    USE SIGNAL ;
    SHAPE ABUTMENT ;
    PORT
      LAYER M3 ;
      RECT 10.791 49.497 10.809 49.551 ;
    END
  END r0_rd_out[61]
  PIN r0_rd_out[62]
    DIRECTION OUTPUT ;
    USE SIGNAL ;
    SHAPE ABUTMENT ;
    PORT
      LAYER M3 ;
      RECT 11.295 49.497 11.313 49.551 ;
    END
  END r0_rd_out[62]
  PIN r0_rd_out[63]
    DIRECTION OUTPUT ;
    USE SIGNAL ;
    SHAPE ABUTMENT ;
    PORT
      LAYER M3 ;
      RECT 11.799 49.497 11.817 49.551 ;
    END
  END r0_rd_out[63]
  PIN r0_rd_out[64]
    DIRECTION OUTPUT ;
    USE SIGNAL ;
    SHAPE ABUTMENT ;
    PORT
      LAYER M3 ;
      RECT 12.303 49.497 12.321 49.551 ;
    END
  END r0_rd_out[64]
  PIN r0_rd_out[65]
    DIRECTION OUTPUT ;
    USE SIGNAL ;
    SHAPE ABUTMENT ;
    PORT
      LAYER M3 ;
      RECT 12.807 49.497 12.825 49.551 ;
    END
  END r0_rd_out[65]
  PIN r0_rd_out[66]
    DIRECTION OUTPUT ;
    USE SIGNAL ;
    SHAPE ABUTMENT ;
    PORT
      LAYER M3 ;
      RECT 13.311 49.497 13.329 49.551 ;
    END
  END r0_rd_out[66]
  PIN r0_rd_out[67]
    DIRECTION OUTPUT ;
    USE SIGNAL ;
    SHAPE ABUTMENT ;
    PORT
      LAYER M3 ;
      RECT 13.815 49.497 13.833 49.551 ;
    END
  END r0_rd_out[67]
  PIN r0_rd_out[68]
    DIRECTION OUTPUT ;
    USE SIGNAL ;
    SHAPE ABUTMENT ;
    PORT
      LAYER M3 ;
      RECT 14.319 49.497 14.337 49.551 ;
    END
  END r0_rd_out[68]
  PIN r0_rd_out[69]
    DIRECTION OUTPUT ;
    USE SIGNAL ;
    SHAPE ABUTMENT ;
    PORT
      LAYER M3 ;
      RECT 14.823 49.497 14.841 49.551 ;
    END
  END r0_rd_out[69]
  PIN r0_rd_out[70]
    DIRECTION OUTPUT ;
    USE SIGNAL ;
    SHAPE ABUTMENT ;
    PORT
      LAYER M3 ;
      RECT 15.327 49.497 15.345 49.551 ;
    END
  END r0_rd_out[70]
  PIN r0_rd_out[71]
    DIRECTION OUTPUT ;
    USE SIGNAL ;
    SHAPE ABUTMENT ;
    PORT
      LAYER M3 ;
      RECT 15.831 49.497 15.849 49.551 ;
    END
  END r0_rd_out[71]
  PIN r0_rd_out[72]
    DIRECTION OUTPUT ;
    USE SIGNAL ;
    SHAPE ABUTMENT ;
    PORT
      LAYER M3 ;
      RECT 16.335 49.497 16.353 49.551 ;
    END
  END r0_rd_out[72]
  PIN r0_rd_out[73]
    DIRECTION OUTPUT ;
    USE SIGNAL ;
    SHAPE ABUTMENT ;
    PORT
      LAYER M3 ;
      RECT 16.839 49.497 16.857 49.551 ;
    END
  END r0_rd_out[73]
  PIN r0_rd_out[74]
    DIRECTION OUTPUT ;
    USE SIGNAL ;
    SHAPE ABUTMENT ;
    PORT
      LAYER M3 ;
      RECT 17.343 49.497 17.361 49.551 ;
    END
  END r0_rd_out[74]
  PIN r0_rd_out[75]
    DIRECTION OUTPUT ;
    USE SIGNAL ;
    SHAPE ABUTMENT ;
    PORT
      LAYER M3 ;
      RECT 17.847 49.497 17.865 49.551 ;
    END
  END r0_rd_out[75]
  PIN r0_rd_out[76]
    DIRECTION OUTPUT ;
    USE SIGNAL ;
    SHAPE ABUTMENT ;
    PORT
      LAYER M3 ;
      RECT 18.351 49.497 18.369 49.551 ;
    END
  END r0_rd_out[76]
  PIN r0_rd_out[77]
    DIRECTION OUTPUT ;
    USE SIGNAL ;
    SHAPE ABUTMENT ;
    PORT
      LAYER M3 ;
      RECT 18.855 49.497 18.873 49.551 ;
    END
  END r0_rd_out[77]
  PIN r0_rd_out[78]
    DIRECTION OUTPUT ;
    USE SIGNAL ;
    SHAPE ABUTMENT ;
    PORT
      LAYER M3 ;
      RECT 19.359 49.497 19.377 49.551 ;
    END
  END r0_rd_out[78]
  PIN r0_rd_out[79]
    DIRECTION OUTPUT ;
    USE SIGNAL ;
    SHAPE ABUTMENT ;
    PORT
      LAYER M3 ;
      RECT 19.863 49.497 19.881 49.551 ;
    END
  END r0_rd_out[79]
  PIN w0_addr_in[0]
    DIRECTION INPUT ;
    USE SIGNAL ;
    SHAPE ABUTMENT ;
    PORT
      LAYER M4 ;
      RECT 0.000 34.836 0.072 34.860 ;
    END
  END w0_addr_in[0]
  PIN w0_addr_in[1]
    DIRECTION INPUT ;
    USE SIGNAL ;
    SHAPE ABUTMENT ;
    PORT
      LAYER M4 ;
      RECT 0.000 36.564 0.072 36.588 ;
    END
  END w0_addr_in[1]
  PIN w0_addr_in[2]
    DIRECTION INPUT ;
    USE SIGNAL ;
    SHAPE ABUTMENT ;
    PORT
      LAYER M4 ;
      RECT 0.000 38.292 0.072 38.316 ;
    END
  END w0_addr_in[2]
  PIN w0_addr_in[3]
    DIRECTION INPUT ;
    USE SIGNAL ;
    SHAPE ABUTMENT ;
    PORT
      LAYER M4 ;
      RECT 0.000 40.020 0.072 40.044 ;
    END
  END w0_addr_in[3]
  PIN w0_addr_in[4]
    DIRECTION INPUT ;
    USE SIGNAL ;
    SHAPE ABUTMENT ;
    PORT
      LAYER M4 ;
      RECT 24.034 34.836 24.106 34.860 ;
    END
  END w0_addr_in[4]
  PIN w0_addr_in[5]
    DIRECTION INPUT ;
    USE SIGNAL ;
    SHAPE ABUTMENT ;
    PORT
      LAYER M4 ;
      RECT 24.034 36.564 24.106 36.588 ;
    END
  END w0_addr_in[5]
  PIN w0_addr_in[6]
    DIRECTION INPUT ;
    USE SIGNAL ;
    SHAPE ABUTMENT ;
    PORT
      LAYER M4 ;
      RECT 24.034 38.292 24.106 38.316 ;
    END
  END w0_addr_in[6]
  PIN w0_addr_in[7]
    DIRECTION INPUT ;
    USE SIGNAL ;
    SHAPE ABUTMENT ;
    PORT
      LAYER M4 ;
      RECT 24.034 40.020 24.106 40.044 ;
    END
  END w0_addr_in[7]
  PIN r0_addr_in[0]
    DIRECTION INPUT ;
    USE SIGNAL ;
    SHAPE ABUTMENT ;
    PORT
      LAYER M4 ;
      RECT 0.000 41.748 0.072 41.772 ;
    END
  END r0_addr_in[0]
  PIN r0_addr_in[1]
    DIRECTION INPUT ;
    USE SIGNAL ;
    SHAPE ABUTMENT ;
    PORT
      LAYER M4 ;
      RECT 0.000 43.476 0.072 43.500 ;
    END
  END r0_addr_in[1]
  PIN r0_addr_in[2]
    DIRECTION INPUT ;
    USE SIGNAL ;
    SHAPE ABUTMENT ;
    PORT
      LAYER M4 ;
      RECT 0.000 45.204 0.072 45.228 ;
    END
  END r0_addr_in[2]
  PIN r0_addr_in[3]
    DIRECTION INPUT ;
    USE SIGNAL ;
    SHAPE ABUTMENT ;
    PORT
      LAYER M4 ;
      RECT 0.000 46.932 0.072 46.956 ;
    END
  END r0_addr_in[3]
  PIN r0_addr_in[4]
    DIRECTION INPUT ;
    USE SIGNAL ;
    SHAPE ABUTMENT ;
    PORT
      LAYER M4 ;
      RECT 24.034 41.748 24.106 41.772 ;
    END
  END r0_addr_in[4]
  PIN r0_addr_in[5]
    DIRECTION INPUT ;
    USE SIGNAL ;
    SHAPE ABUTMENT ;
    PORT
      LAYER M4 ;
      RECT 24.034 43.476 24.106 43.500 ;
    END
  END r0_addr_in[5]
  PIN r0_addr_in[6]
    DIRECTION INPUT ;
    USE SIGNAL ;
    SHAPE ABUTMENT ;
    PORT
      LAYER M4 ;
      RECT 24.034 45.204 24.106 45.228 ;
    END
  END r0_addr_in[6]
  PIN r0_addr_in[7]
    DIRECTION INPUT ;
    USE SIGNAL ;
    SHAPE ABUTMENT ;
    PORT
      LAYER M4 ;
      RECT 24.034 46.932 24.106 46.956 ;
    END
  END r0_addr_in[7]
  PIN w0_we_in
    DIRECTION INPUT ;
    USE SIGNAL ;
    SHAPE ABUTMENT ;
    PORT
      LAYER M3 ;
      RECT 20.367 49.497 20.385 49.551 ;
    END
  END w0_we_in
  PIN w0_ce_in
    DIRECTION INPUT ;
    USE SIGNAL ;
    SHAPE ABUTMENT ;
    PORT
      LAYER M3 ;
      RECT 20.871 49.497 20.889 49.551 ;
    END
  END w0_ce_in
  PIN w0_clk
    DIRECTION INPUT ;
    USE SIGNAL ;
    SHAPE ABUTMENT ;
    PORT
      LAYER M3 ;
      RECT 21.375 49.497 21.393 49.551 ;
    END
  END w0_clk
  PIN r0_ce_in
    DIRECTION INPUT ;
    USE SIGNAL ;
    SHAPE ABUTMENT ;
    PORT
      LAYER M3 ;
      RECT 21.879 49.497 21.897 49.551 ;
    END
  END r0_ce_in
  PIN r0_clk
    DIRECTION INPUT ;
    USE SIGNAL ;
    SHAPE ABUTMENT ;
    PORT
      LAYER M3 ;
      RECT 22.383 49.497 22.401 49.551 ;
    END
  END r0_clk
  PIN VSS
    DIRECTION INOUT ;
    USE GROUND ;
    PORT
      LAYER M4 ;
      RECT 0.216 0.240 23.890 0.336 ;
      RECT 0.216 1.008 23.890 1.104 ;
      RECT 0.216 1.776 23.890 1.872 ;
      RECT 0.216 2.544 23.890 2.640 ;
      RECT 0.216 3.312 23.890 3.408 ;
      RECT 0.216 4.080 23.890 4.176 ;
      RECT 0.216 4.848 23.890 4.944 ;
      RECT 0.216 5.616 23.890 5.712 ;
      RECT 0.216 6.384 23.890 6.480 ;
      RECT 0.216 7.152 23.890 7.248 ;
      RECT 0.216 7.920 23.890 8.016 ;
      RECT 0.216 8.688 23.890 8.784 ;
      RECT 0.216 9.456 23.890 9.552 ;
      RECT 0.216 10.224 23.890 10.320 ;
      RECT 0.216 10.992 23.890 11.088 ;
      RECT 0.216 11.760 23.890 11.856 ;
      RECT 0.216 12.528 23.890 12.624 ;
      RECT 0.216 13.296 23.890 13.392 ;
      RECT 0.216 14.064 23.890 14.160 ;
      RECT 0.216 14.832 23.890 14.928 ;
      RECT 0.216 15.600 23.890 15.696 ;
      RECT 0.216 16.368 23.890 16.464 ;
      RECT 0.216 17.136 23.890 17.232 ;
      RECT 0.216 17.904 23.890 18.000 ;
      RECT 0.216 18.672 23.890 18.768 ;
      RECT 0.216 19.440 23.890 19.536 ;
      RECT 0.216 20.208 23.890 20.304 ;
      RECT 0.216 20.976 23.890 21.072 ;
      RECT 0.216 21.744 23.890 21.840 ;
      RECT 0.216 22.512 23.890 22.608 ;
      RECT 0.216 23.280 23.890 23.376 ;
      RECT 0.216 24.048 23.890 24.144 ;
      RECT 0.216 24.816 23.890 24.912 ;
      RECT 0.216 25.584 23.890 25.680 ;
      RECT 0.216 26.352 23.890 26.448 ;
      RECT 0.216 27.120 23.890 27.216 ;
      RECT 0.216 27.888 23.890 27.984 ;
      RECT 0.216 28.656 23.890 28.752 ;
      RECT 0.216 29.424 23.890 29.520 ;
      RECT 0.216 30.192 23.890 30.288 ;
      RECT 0.216 30.960 23.890 31.056 ;
      RECT 0.216 31.728 23.890 31.824 ;
      RECT 0.216 32.496 23.890 32.592 ;
      RECT 0.216 33.264 23.890 33.360 ;
      RECT 0.216 34.032 23.890 34.128 ;
      RECT 0.216 34.800 23.890 34.896 ;
      RECT 0.216 35.568 23.890 35.664 ;
      RECT 0.216 36.336 23.890 36.432 ;
      RECT 0.216 37.104 23.890 37.200 ;
      RECT 0.216 37.872 23.890 37.968 ;
      RECT 0.216 38.640 23.890 38.736 ;
      RECT 0.216 39.408 23.890 39.504 ;
      RECT 0.216 40.176 23.890 40.272 ;
      RECT 0.216 40.944 23.890 41.040 ;
      RECT 0.216 41.712 23.890 41.808 ;
      RECT 0.216 42.480 23.890 42.576 ;
      RECT 0.216 43.248 23.890 43.344 ;
      RECT 0.216 44.016 23.890 44.112 ;
      RECT 0.216 44.784 23.890 44.880 ;
      RECT 0.216 45.552 23.890 45.648 ;
      RECT 0.216 46.320 23.890 46.416 ;
      RECT 0.216 47.088 23.890 47.184 ;
      RECT 0.216 47.856 23.890 47.952 ;
      RECT 0.216 48.624 23.890 48.720 ;
      RECT 0.216 49.392 23.890 49.488 ;
    END
  END VSS
  PIN VDD
    DIRECTION INOUT ;
    USE POWER ;
    PORT
      LAYER M4 ;
      RECT 0.216 0.240 23.890 0.336 ;
      RECT 0.216 1.008 23.890 1.104 ;
      RECT 0.216 1.776 23.890 1.872 ;
      RECT 0.216 2.544 23.890 2.640 ;
      RECT 0.216 3.312 23.890 3.408 ;
      RECT 0.216 4.080 23.890 4.176 ;
      RECT 0.216 4.848 23.890 4.944 ;
      RECT 0.216 5.616 23.890 5.712 ;
      RECT 0.216 6.384 23.890 6.480 ;
      RECT 0.216 7.152 23.890 7.248 ;
      RECT 0.216 7.920 23.890 8.016 ;
      RECT 0.216 8.688 23.890 8.784 ;
      RECT 0.216 9.456 23.890 9.552 ;
      RECT 0.216 10.224 23.890 10.320 ;
      RECT 0.216 10.992 23.890 11.088 ;
      RECT 0.216 11.760 23.890 11.856 ;
      RECT 0.216 12.528 23.890 12.624 ;
      RECT 0.216 13.296 23.890 13.392 ;
      RECT 0.216 14.064 23.890 14.160 ;
      RECT 0.216 14.832 23.890 14.928 ;
      RECT 0.216 15.600 23.890 15.696 ;
      RECT 0.216 16.368 23.890 16.464 ;
      RECT 0.216 17.136 23.890 17.232 ;
      RECT 0.216 17.904 23.890 18.000 ;
      RECT 0.216 18.672 23.890 18.768 ;
      RECT 0.216 19.440 23.890 19.536 ;
      RECT 0.216 20.208 23.890 20.304 ;
      RECT 0.216 20.976 23.890 21.072 ;
      RECT 0.216 21.744 23.890 21.840 ;
      RECT 0.216 22.512 23.890 22.608 ;
      RECT 0.216 23.280 23.890 23.376 ;
      RECT 0.216 24.048 23.890 24.144 ;
      RECT 0.216 24.816 23.890 24.912 ;
      RECT 0.216 25.584 23.890 25.680 ;
      RECT 0.216 26.352 23.890 26.448 ;
      RECT 0.216 27.120 23.890 27.216 ;
      RECT 0.216 27.888 23.890 27.984 ;
      RECT 0.216 28.656 23.890 28.752 ;
      RECT 0.216 29.424 23.890 29.520 ;
      RECT 0.216 30.192 23.890 30.288 ;
      RECT 0.216 30.960 23.890 31.056 ;
      RECT 0.216 31.728 23.890 31.824 ;
      RECT 0.216 32.496 23.890 32.592 ;
      RECT 0.216 33.264 23.890 33.360 ;
      RECT 0.216 34.032 23.890 34.128 ;
      RECT 0.216 34.800 23.890 34.896 ;
      RECT 0.216 35.568 23.890 35.664 ;
      RECT 0.216 36.336 23.890 36.432 ;
      RECT 0.216 37.104 23.890 37.200 ;
      RECT 0.216 37.872 23.890 37.968 ;
      RECT 0.216 38.640 23.890 38.736 ;
      RECT 0.216 39.408 23.890 39.504 ;
      RECT 0.216 40.176 23.890 40.272 ;
      RECT 0.216 40.944 23.890 41.040 ;
      RECT 0.216 41.712 23.890 41.808 ;
      RECT 0.216 42.480 23.890 42.576 ;
      RECT 0.216 43.248 23.890 43.344 ;
      RECT 0.216 44.016 23.890 44.112 ;
      RECT 0.216 44.784 23.890 44.880 ;
      RECT 0.216 45.552 23.890 45.648 ;
      RECT 0.216 46.320 23.890 46.416 ;
      RECT 0.216 47.088 23.890 47.184 ;
      RECT 0.216 47.856 23.890 47.952 ;
      RECT 0.216 48.624 23.890 48.720 ;
      RECT 0.216 49.392 23.890 49.488 ;
    END
  END VDD
  OBS
    LAYER M1 ;
    RECT 0 0 24.106 49.551 ;
    LAYER M2 ;
    RECT 0 0 24.106 49.551 ;
    LAYER M3 ;
    RECT 0 0 24.106 49.551 ;
    LAYER M4 ;
    RECT 0 0 24.106 49.551 ;
  END
END fakeram_80x256_1r1w

END LIBRARY
